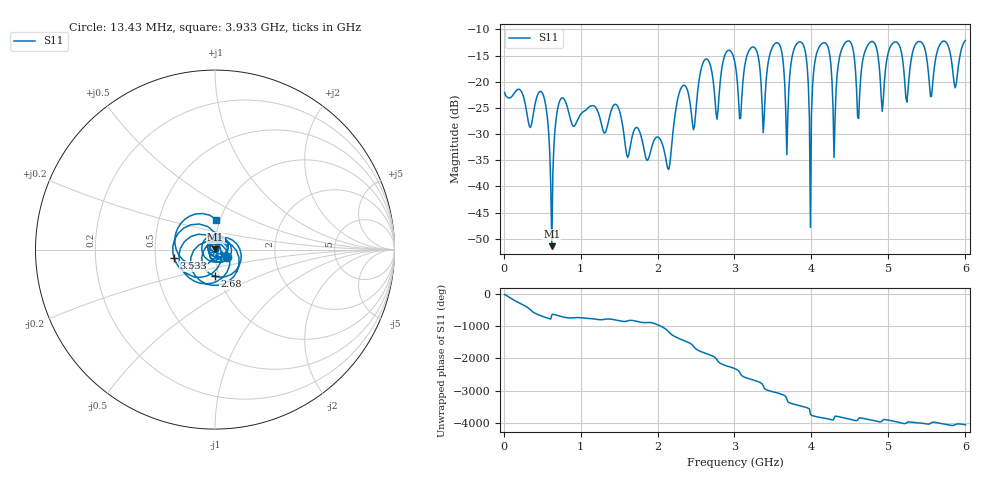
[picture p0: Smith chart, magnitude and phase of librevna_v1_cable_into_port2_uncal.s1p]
! LibreVNA V1 Rev.B, LibreVNA-GUI/firmware 1.6.5, no calibration active (raw data)
! DUT: 15 cm coax from port 1 into port 2 (port 2 acts as a 50 ohm termination) - radiates nothing
! IFBW 1 kHz, -20 dBm, overview sweep decimated 10:1
# HZ S RI R 50
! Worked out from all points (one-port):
!   450 points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, 13.43 MHz to 6 GHz, reference 50 ohm
!   lowest |S11| = -51.4 dB at 626.8 MHz (marker M1), VSWR 1.01, Z = 50.1 + j0.237 ohm
!   |S11| at or under -10 dB: start of sweep to end of sweep
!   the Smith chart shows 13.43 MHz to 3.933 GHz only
!   S11 on the Smith chart (normalised r, x): 13.43 MHz: 1.14, -0.09; 2.68 GHz: 0.95, -0.29; 3.533 GHz: 0.63, -0.06; 3.933 GHz: 0.96, +0.33
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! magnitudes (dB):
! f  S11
! 13.43 MHz  -22.1
! 506.8 MHz  -22.3
! 626.8 MHz  -51.4
! 773.4 MHz  -23.1
! 1.52 GHz  -26.4
! 2.133 GHz  -36.6
! 2.267 GHz  -23.0
! 2.467 GHz  -29.2
! 2.68 GHz  -16.6
! 2.773 GHz  -27.2
! 3.013 GHz  -17.0
! 3.08 GHz  -27.0
! 3.267 GHz  -13.6
! 3.373 GHz  -29.7
! 3.533 GHz  -12.6
! 3.68 GHz  -34.0
! 3.76 GHz  -14.5
! 3.933 GHz  -15.5
! 3.987 GHz  -47.8
! 4.093 GHz  -13.6
! 4.293 GHz  -34.5
! 4.507 GHz  -12.4
! 4.613 GHz  -27.0
! 4.773 GHz  -12.4
! 4.92 GHz  -25.7
! 5.08 GHz  -12.4
! 5.253 GHz  -21.9
! 6 GHz  -12.1
